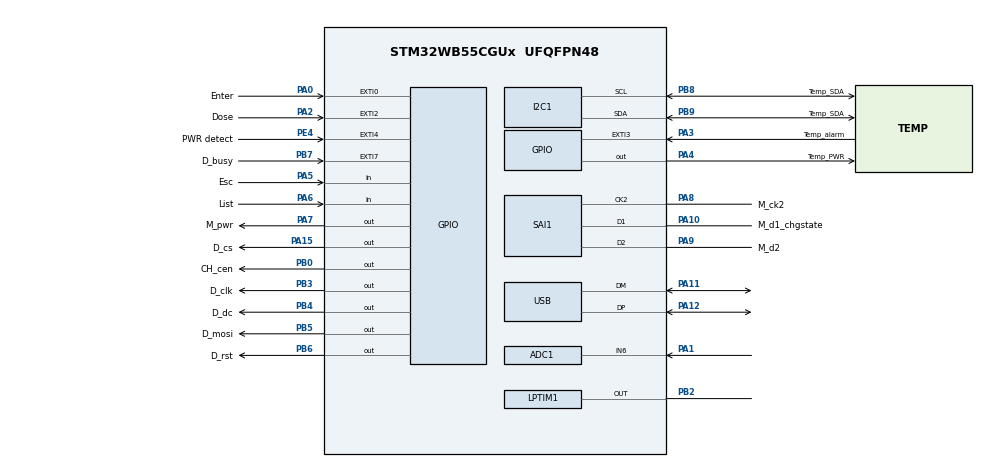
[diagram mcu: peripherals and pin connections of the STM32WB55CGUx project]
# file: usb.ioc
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ADC1.Channel-0\#ChannelRegularConversion=ADC_CHANNEL_6
ADC1.NbrOfConversion=1
ADC1.NbrOfConversionFlag=1
ADC1.OffsetNumber-0\#ChannelRegularConversion=ADC_OFFSET_NONE
ADC1.Rank-0\#ChannelRegularConversion=1
ADC1.SamplingTime-0\#ChannelRegularConversion=ADC_SAMPLETIME_640CYCLES_5
ADC1.master=1
Dma.Request0=SAI1_A
Dma.SAI1_A.0.Direction=DMA_PERIPH_TO_MEMORY
Dma.SAI1_A.0.EventEnable=DISABLE
Dma.SAI1_A.0.Instance=DMA1_Channel1
Dma.SAI1_A.0.MemDataAlignment=DMA_MDATAALIGN_WORD
Dma.SAI1_A.0.MemInc=DMA_MINC_ENABLE
Dma.SAI1_A.0.Mode=DMA_NORMAL
Dma.SAI1_A.0.PeriphDataAlignment=DMA_PDATAALIGN_WORD
Dma.SAI1_A.0.PeriphInc=DMA_PINC_DISABLE
Dma.SAI1_A.0.Polarity=HAL_DMAMUX_REQ_GEN_RISING
Dma.SAI1_A.0.Priority=DMA_PRIORITY_HIGH
Dma.SAI1_A.0.RequestNumber=1
Dma.SAI1_A.0.SignalID=NONE
Dma.SAI1_A.0.SyncEnable=DISABLE
Dma.SAI1_A.0.SyncPolarity=HAL_DMAMUX_SYNC_NO_EVENT
Dma.SAI1_A.0.SyncRequestNumber=1
Dma.SAI1_A.0.SyncSignalID=NONE
FATFS._FS_LOCK=1
FATFS._FS_MINIMIZE=2
I2C1.Speed=50
I2C1.Timing=0x10503EF9
LPTIM1.ClockPrescaler=LPTIM_PRESCALER_DIV32
Mcu.Family=STM32WB
Mcu.Name=STM32WB55CGUx
Mcu.Package=UFQFPN48
NVIC.DMA1_Channel1_IRQn=true\:0\:0\:false\:false\:true\:false\:true\:true
NVIC.EXTI0_IRQn=true\:0\:0\:false\:false\:true\:true\:true\:true
NVIC.EXTI2_IRQn=true\:0\:0\:false\:false\:true\:true\:true\:true
NVIC.EXTI3_IRQn=true\:0\:0\:false\:false\:true\:true\:true\:true
NVIC.EXTI4_IRQn=true\:0\:0\:false\:false\:true\:true\:true\:true
NVIC.EXTI9_5_IRQn=true\:0\:0\:false\:false\:true\:true\:true\:true
NVIC.FPU_IRQn=true\:0\:0\:false\:false\:true\:true\:false\:true
NVIC.PriorityGroup=NVIC_PRIORITYGROUP_4
NVIC.RTC_Alarm_IRQn=true\:0\:0\:false\:false\:true\:true\:true\:true
NVIC.RTC_WKUP_IRQn=true\:0\:0\:false\:false\:true\:true\:true\:true
NVIC.SAI1_IRQn=true\:0\:0\:false\:false\:true\:true\:true\:true
NVIC.USB_HP_IRQn=true\:0\:0\:false\:false\:true\:true\:true\:true
NVIC.USB_LP_IRQn=true\:0\:0\:false\:false\:true\:true\:true\:true
OSC_IN.Mode=HSE-External-Oscillator
OSC_IN.Signal=RCC_OSC_IN
OSC_OUT.Mode=HSE-External-Oscillator
OSC_OUT.Signal=RCC_OSC_OUT
PA0.GPIO_Label=Enter
PA0.Signal=GPXTI0
PA1.Signal=ADCx_IN6
PA10.GPIO_Label=M_d1_chgstate
PA10.Mode=PDM_Master_Mode_CK2
PA10.Signal=SAI1_D1
PA11.Mode=Device
PA11.Signal=USB_DM
PA12.Mode=Device
PA12.Signal=USB_DP
PA13.Mode=Serial_Wire
PA13.Signal=SYS_JTMS-SWDIO
PA14.Mode=Serial_Wire
PA14.Signal=SYS_JTCK-SWCLK
PA15.GPIO_Label=D_cs
PA15.Signal=GPIO_Output
PA2.GPIO_Label=Dose
PA2.GPIO_ModeDefaultEXTI=GPIO_MODE_IT_RISING_FALLING
PA2.GPIO_PuPd=GPIO_PULLUP
PA2.Signal=GPXTI2
PA3.GPIO_Label=Temp_alarm
PA3.GPIO_ModeDefaultEXTI=GPIO_MODE_IT_FALLING
PA3.GPIO_PuPd=GPIO_PULLUP
PA3.Signal=GPXTI3
PA4.GPIO_Label=Temp_PWR
PA4.GPIO_PuPd=GPIO_NOPULL
PA4.Signal=GPIO_Output
PA5.GPIO_Label=Esc
PA5.GPIO_PuPd=GPIO_PULLUP
PA5.Signal=GPIO_Input
PA6.GPIO_Label=List
PA6.GPIO_PuPd=GPIO_PULLUP
PA6.Signal=GPIO_Input
PA7.GPIO_Label=M_pwr
PA7.Signal=GPIO_Output
PA8.GPIO_Label=M_ck2
PA8.Mode=PDM_Master_Mode_CK2
PA8.Signal=SAI1_CK2
PA9.GPIO_Label=M_d2
PA9.Mode=3_4_MicroPhones
PA9.Signal=SAI1_D2
PB0.GPIO_Label=CH_cen
PB0.Signal=GPIO_Output
PB2.Mode=WaveformGeneration
PB2.Signal=LPTIM1_OUT
PB3.GPIO_Label=D_clk
PB3.Signal=GPIO_Output
PB4.GPIO_Label=D_dc
PB4.Signal=GPIO_Output
PB5.GPIO_Label=D_mosi
PB5.Signal=GPIO_Output
PB6.GPIO_Label=D_rst
PB6.Signal=GPIO_Output
PB7.GPIO_Label=D_busy
PB7.Signal=GPXTI7
PB8.GPIO_Label=Temp_SDA
PB8.GPIO_Pu=GPIO_PULLUP
PB8.Mode=I2C
PB8.Signal=I2C1_SCL
PB9.GPIO_Label=Temp_SDA
PB9.GPIO_Pu=GPIO_PULLUP
PB9.Mode=I2C
PB9.Signal=I2C1_SDA
PC14-OSC32_IN.Mode=LSE-External-Oscillator
PC14-OSC32_IN.Signal=RCC_OSC32_IN
PC15-OSC32_OUT.Mode=LSE-External-Oscillator
PC15-OSC32_OUT.Signal=RCC_OSC32_OUT
PE4.GPIO_Label=PWR detect
PE4.GPIO_ModeDefaultEXTI=GPIO_MODE_IT_RISING_FALLING
PE4.Signal=GPXTI4
ProjectManager.HeapSize=0x200
ProjectManager.StackSize=0x400
ProjectManager.TargetToolchain=STM32CubeIDE
RCC.ADCCLockSelection=RCC_ADCCLKSOURCE_SYSCLK
RCC.ADCFreq_Value=32000000
RCC.AHB2CLKDivider=RCC_SYSCLK_DIV8
RCC.AHBFreq_Value=32000000
RCC.APB1Freq_Value=32000000
RCC.APB1TimFreq_Value=32000000
RCC.APB2Freq_Value=32000000
RCC.APB2TimFreq_Value=32000000
RCC.APB3Freq_Value=16000000
RCC.CK48CLockSelection=RCC_USBCLKSOURCE_PLL
RCC.Cortex2_Div=SYSTICK_CLKSOURCE_HCLK_DIV8
RCC.CortexFreq_Value=32000000
RCC.EnableCSSLSE=true
RCC.HCLKFreq_Value=32000000
RCC.HSE_VALUE=32000000
RCC.HSI48_VALUE=48000000
RCC.HSI_VALUE=16000000
RCC.LSISource1=RCC_LSCOSOURCE_LSI2
RCC.MSIClockRange=RCC_MSIRANGE_8
RCC.PLLN=12
RCC.PLLP=RCC_PLLP_DIV4
RCC.PLLQ=RCC_PLLQ_DIV4
RCC.PLLR=RCC_PLLR_DIV6
RCC.PLLSAI1N=12
RCC.PLLSAI1P=RCC_PLLP_DIV4
RCC.PLLSAI1Q=RCC_PLLQ_DIV4
RCC.PLLSAI1R=RCC_PLLR_DIV4
RCC.RTCClockSelection=RCC_RTCCLKSOURCE_LSE
RCC.SMPSCLockSelection=RCC_SMPSCLKSOURCE_MSI
RCC.SYSCLKFreq_VALUE=32000000
RCC.SYSCLKSource=RCC_SYSCLKSOURCE_PLLCLK
RCC.USBFreq_Value=48000000
RCC.VCOOutputFreq_Value=192000000
RTC.Alarm-Alarm\ A=RTC_ALARM_A
SAI1.Activation=ENABLE
SAI1.AudioFrequency-PDM_Master_Mode_CK2=SAI_AUDIO_FREQUENCY_44K
SAI1.DataSize-PDM_Master_Mode_CK2=SAI_DATASIZE_8
SAI1.ErrorAudioFreq-PDM_Master_Mode_CK2=6.29 %
SAI1.FIFOThreshold-PDM_Master_Mode_CK2=SAI_FIFOTHRESHOLD_HF
SAI1.FSOffset-PDM_Master_Mode_CK2=SAI_FS_BEFOREFIRSTBIT
SAI1.FrameLength-PDM_Master_Mode_CK2=32
SAI1.Instance-PDM_Master_Mode_CK2=SAI$Index_Block_A
SAI1.MClockEnable-PDM_Master_Mode_CK2=SAI_MASTERCLOCK_DISABLE
SAI1.RealAudioFreq-PDM_Master_Mode_CK2=46.875 KHz
SAI1.SlotActive-PDM_Master_Mode_CK2=0x0000FFFF
SAI1.SlotNumber-PDM_Master_Mode_CK2=4
SAI1.SlotSize-PDM_Master_Mode_CK2=SAI_SLOTSIZE_DATASIZE
SAI1.VirtualMode-PDM_Master_Mode_CK2=VM_MASTER
SAI1.VirtualProtocol-PDM_Master_Mode_CK2=VM_PDM_PROTOCOL
SAI1.VirtualSlotActive-PDM_Master_Mode_CK2=SAI_SLOTACTIVE_ALL
SH.ADCx_IN6.0=ADC1_IN6,IN6-Single-Ended
USB_DEVICE.CLASS_NAME_FS=MSC
USB_DEVICE.VirtualMode=Msc
USB_DEVICE.VirtualModeFS=Msc_FS
VP_ADC1_Vref_Input.Mode=IN-Vrefint
VP_CRC_VS_CRC.Mode=CRC_Activate
VP_FATFS_VS_Generic.Mode=User_defined
VP_LPTIM1_VS_LPTIM_counterModeInternalClock.Mode=Counts__internal_clock_event_00
VP_MEMORYMAP_VS_MEMORYMAP.Mode=CurAppReg
VP_RTC_VS_RTC_Activate.Mode=RTC_Enabled
VP_RTC_VS_RTC_Alarm_A_Intern.Mode=Alarm A
VP_RTC_VS_RTC_Calendar.Mode=RTC_Calendar
VP_RTC_VS_RTC_WakeUp_intern.Mode=WakeUp
VP_USB_DEVICE_VS_USB_DEVICE_MSC_FS.Mode=MSC_FS
board=custom

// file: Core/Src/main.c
/* USER CODE BEGIN Header */
/**
  ******************************************************************************
  * @file           : main.c
  * @brief          : Main program body
  ******************************************************************************
  * @attention
  *
  * Copyright (c) 2025 STMicroelectronics.
  * All rights reserved.
  *
  * This software is licensed under terms that can be found in the LICENSE file
  * in the root directory of this software component.
  * If no LICENSE file comes with this software, it is provided AS-IS.
  *
  ******************************************************************************
  */
/* USER CODE END Header */
#include "main.h"
#include "app_fatfs.h"
#include "usb_device.h"

/* USER CODE BEGIN Includes */
#include "app_runtime.h"
/* main.c keeps CubeMX-generated peripheral bring-up; app_runtime.c owns the application flow. */
/* USER CODE END Includes */

ADC_HandleTypeDef hadc1;

CRC_HandleTypeDef hcrc;

I2C_HandleTypeDef hi2c1;

LPTIM_HandleTypeDef hlptim1;

RTC_HandleTypeDef hrtc;

SAI_HandleTypeDef hsai_BlockA1;
DMA_HandleTypeDef hdma_sai1_a;

void SystemClock_Config(void);
void PeriphCommonClock_Config(void);
static void MX_GPIO_Init(void);
static void MX_DMA_Init(void);
static void MX_LPTIM1_Init(void);
static void MX_ADC1_Init(void);
static void MX_RTC_Init(void);
static void MX_I2C1_Init(void);
static void MX_SAI1_Init(void);
static void MX_CRC_Init(void);

int main(void)
{

  /* MCU Configuration--------------------------------------------------------*/

  /* Reset of all peripherals, Initializes the Flash interface and the Systick. */
  HAL_Init();

  /* Configure the system clock */
  SystemClock_Config();

  /* Configure the peripherals common clocks */
  PeriphCommonClock_Config();

  /* Initialize all configured peripherals */
  MX_GPIO_Init();
  MX_DMA_Init();
  MX_LPTIM1_Init();
  if (MX_FATFS_Init() != APP_OK) {
    Error_Handler();
  }
  MX_ADC1_Init();
  MX_RTC_Init();
  MX_I2C1_Init();
  MX_SAI1_Init();
  MX_CRC_Init();
  /* USER CODE BEGIN 2 */
  /* Hand control to the higher-level runtime once all HAL handles exist. */
  if (!app_runtime_init(&hi2c1, &hlptim1)) {
    Error_Handler();
  }
  /* USER CODE END 2 */

  /* Infinite loop */
  while (1)
  {

    /* USER CODE BEGIN 3 */
    /* The application is organized as one cooperative superloop tick. */
    app_runtime_tick();
  }
  /* USER CODE END 3 */
}

void SystemClock_Config(void)
{
  RCC_OscInitTypeDef RCC_OscInitStruct = {0};
  RCC_ClkInitTypeDef RCC_ClkInitStruct = {0};

  /** Configure LSE Drive Capability
  */
  HAL_PWR_EnableBkUpAccess();
  __HAL_RCC_LSEDRIVE_CONFIG(RCC_LSEDRIVE_MEDIUMHIGH);

  /** Configure the main internal regulator output voltage
  */
  __HAL_PWR_VOLTAGESCALING_CONFIG(PWR_REGULATOR_VOLTAGE_SCALE1);

  /** Initializes the RCC Oscillators according to the specified parameters
  * in the RCC_OscInitTypeDef structure.
  */
  RCC_OscInitStruct.OscillatorType = RCC_OSCILLATORTYPE_HSI|RCC_OSCILLATORTYPE_HSE
                              |RCC_OSCILLATORTYPE_LSE|RCC_OSCILLATORTYPE_MSI;
  RCC_OscInitStruct.HSEState = RCC_HSE_ON;
  RCC_OscInitStruct.LSEState = RCC_LSE_ON;
  RCC_OscInitStruct.HSIState = RCC_HSI_ON;
  RCC_OscInitStruct.MSIState = RCC_MSI_ON;
  RCC_OscInitStruct.HSICalibrationValue = RCC_HSICALIBRATION_DEFAULT;
  RCC_OscInitStruct.MSICalibrationValue = RCC_MSICALIBRATION_DEFAULT;
  RCC_OscInitStruct.MSIClockRange = RCC_MSIRANGE_8;
  RCC_OscInitStruct.PLL.PLLState = RCC_PLL_ON;
  RCC_OscInitStruct.PLL.PLLSource = RCC_PLLSOURCE_MSI;
  RCC_OscInitStruct.PLL.PLLM = RCC_PLLM_DIV1;
  RCC_OscInitStruct.PLL.PLLN = 12;
  RCC_OscInitStruct.PLL.PLLP = RCC_PLLP_DIV4;
  RCC_OscInitStruct.PLL.PLLR = RCC_PLLR_DIV3;
  RCC_OscInitStruct.PLL.PLLQ = RCC_PLLQ_DIV4;
  if (HAL_RCC_OscConfig(&RCC_OscInitStruct) != HAL_OK)
  {
    Error_Handler();
  }

  /** Configure the SYSCLKSource, HCLK, PCLK1 and PCLK2 clocks dividers
  */
  RCC_ClkInitStruct.ClockType = RCC_CLOCKTYPE_HCLK4|RCC_CLOCKTYPE_HCLK2
                              |RCC_CLOCKTYPE_HCLK|RCC_CLOCKTYPE_SYSCLK
                              |RCC_CLOCKTYPE_PCLK1|RCC_CLOCKTYPE_PCLK2;
  RCC_ClkInitStruct.SYSCLKSource = RCC_SYSCLKSOURCE_PLLCLK;
  RCC_ClkInitStruct.AHBCLKDivider = RCC_SYSCLK_DIV1;
  RCC_ClkInitStruct.APB1CLKDivider = RCC_HCLK_DIV1;
  RCC_ClkInitStruct.APB2CLKDivider = RCC_HCLK_DIV1;
  RCC_ClkInitStruct.AHBCLK2Divider = RCC_SYSCLK_DIV8;
  RCC_ClkInitStruct.AHBCLK4Divider = RCC_SYSCLK_DIV1;

  if (HAL_RCC_ClockConfig(&RCC_ClkInitStruct, FLASH_LATENCY_3) != HAL_OK)
  {
    Error_Handler();
  }

  /** Enables the Clock Security System
  */
  HAL_RCCEx_EnableLSECSS();

  /** Enable MSI Auto calibration
  */
  HAL_RCCEx_EnableMSIPLLMode();
}

void PeriphCommonClock_Config(void)
{
  RCC_PeriphCLKInitTypeDef PeriphClkInitStruct = {0};

  /** Initializes the peripherals clock
  */
  PeriphClkInitStruct.PeriphClockSelection = RCC_PERIPHCLK_SMPS;
  PeriphClkInitStruct.SmpsClockSelection = RCC_SMPSCLKSOURCE_MSI;
  PeriphClkInitStruct.SmpsDivSelection = RCC_SMPSCLKDIV_RANGE1;

  if (HAL_RCCEx_PeriphCLKConfig(&PeriphClkInitStruct) != HAL_OK)
  {
    Error_Handler();
  }
}

static void MX_ADC1_Init(void)
{

  ADC_ChannelConfTypeDef sConfig = {0};

  /** Common config
  */
  hadc1.Instance = ADC1;
  hadc1.Init.ClockPrescaler = ADC_CLOCK_ASYNC_DIV1;
  hadc1.Init.Resolution = ADC_RESOLUTION_12B;
  hadc1.Init.DataAlign = ADC_DATAALIGN_RIGHT;
  hadc1.Init.ScanConvMode = ADC_SCAN_DISABLE;
  hadc1.Init.EOCSelection = ADC_EOC_SINGLE_CONV;
  hadc1.Init.LowPowerAutoWait = DISABLE;
  hadc1.Init.ContinuousConvMode = DISABLE;
  hadc1.Init.NbrOfConversion = 1;
  hadc1.Init.DiscontinuousConvMode = DISABLE;
  hadc1.Init.ExternalTrigConv = ADC_SOFTWARE_START;
  hadc1.Init.ExternalTrigConvEdge = ADC_EXTERNALTRIGCONVEDGE_NONE;
  hadc1.Init.DMAContinuousRequests = DISABLE;
  hadc1.Init.Overrun = ADC_OVR_DATA_PRESERVED;
  hadc1.Init.OversamplingMode = DISABLE;
  if (HAL_ADC_Init(&hadc1) != HAL_OK)
  {
    Error_Handler();
  }

  /** Configure Regular Channel
  */
  sConfig.Channel = ADC_CHANNEL_6;
  sConfig.Rank = ADC_REGULAR_RANK_1;
  sConfig.SamplingTime = ADC_SAMPLETIME_640CYCLES_5;
  sConfig.SingleDiff = ADC_SINGLE_ENDED;
  sConfig.OffsetNumber = ADC_OFFSET_NONE;
  sConfig.Offset = 0;
  if (HAL_ADC_ConfigChannel(&hadc1, &sConfig) != HAL_OK)
  {
    Error_Handler();
  }

}

static void MX_CRC_Init(void)
{

  hcrc.Instance = CRC;
  hcrc.Init.DefaultPolynomialUse = DEFAULT_POLYNOMIAL_ENABLE;
  hcrc.Init.DefaultInitValueUse = DEFAULT_INIT_VALUE_ENABLE;
  hcrc.Init.InputDataInversionMode = CRC_INPUTDATA_INVERSION_NONE;
  hcrc.Init.OutputDataInversionMode = CRC_OUTPUTDATA_INVERSION_DISABLE;
  hcrc.InputDataFormat = CRC_INPUTDATA_FORMAT_BYTES;
  if (HAL_CRC_Init(&hcrc) != HAL_OK)
  {
    Error_Handler();
  }

}

static void MX_I2C1_Init(void)
{

  hi2c1.Instance = I2C1;
  hi2c1.Init.Timing = 0x10503EF9;
  hi2c1.Init.OwnAddress1 = 0;
  hi2c1.Init.AddressingMode = I2C_ADDRESSINGMODE_7BIT;
  hi2c1.Init.DualAddressMode = I2C_DUALADDRESS_DISABLE;
  hi2c1.Init.OwnAddress2 = 0;
  hi2c1.Init.OwnAddress2Masks = I2C_OA2_NOMASK;
  hi2c1.Init.GeneralCallMode = I2C_GENERALCALL_DISABLE;
  hi2c1.Init.NoStretchMode = I2C_NOSTRETCH_DISABLE;
  if (HAL_I2C_Init(&hi2c1) != HAL_OK)
  {
    Error_Handler();
  }

  /** Configure Analogue filter
  */
  if (HAL_I2CEx_ConfigAnalogFilter(&hi2c1, I2C_ANALOGFILTER_ENABLE) != HAL_OK)
  {
    Error_Handler();
  }

  /** Configure Digital filter
  */
  if (HAL_I2CEx_ConfigDigitalFilter(&hi2c1, 0) != HAL_OK)
  {
    Error_Handler();
  }

}

static void MX_LPTIM1_Init(void)
{

  hlptim1.Instance = LPTIM1;
  hlptim1.Init.Clock.Source = LPTIM_CLOCKSOURCE_APBCLOCK_LPOSC;
  hlptim1.Init.Clock.Prescaler = LPTIM_PRESCALER_DIV32;
  hlptim1.Init.Trigger.Source = LPTIM_TRIGSOURCE_SOFTWARE;
  hlptim1.Init.OutputPolarity = LPTIM_OUTPUTPOLARITY_HIGH;
  hlptim1.Init.UpdateMode = LPTIM_UPDATE_IMMEDIATE;
  hlptim1.Init.CounterSource = LPTIM_COUNTERSOURCE_INTERNAL;
  hlptim1.Init.Input1Source = LPTIM_INPUT1SOURCE_GPIO;
  hlptim1.Init.Input2Source = LPTIM_INPUT2SOURCE_GPIO;
  if (HAL_LPTIM_Init(&hlptim1) != HAL_OK)
  {
    Error_Handler();
  }

}

static void MX_RTC_Init(void)
{

  RTC_TimeTypeDef sTime = {0};
  RTC_DateTypeDef sDate = {0};
  RTC_AlarmTypeDef sAlarm = {0};

  /** Initialize RTC Only
  */
  hrtc.Instance = RTC;
  hrtc.Init.HourFormat = RTC_HOURFORMAT_24;
  hrtc.Init.AsynchPrediv = 127;
  hrtc.Init.SynchPrediv = 255;
  hrtc.Init.OutPut = RTC_OUTPUT_DISABLE;
  hrtc.Init.OutPutPolarity = RTC_OUTPUT_POLARITY_HIGH;
  hrtc.Init.OutPutType = RTC_OUTPUT_TYPE_OPENDRAIN;
  hrtc.Init.OutPutRemap = RTC_OUTPUT_REMAP_NONE;
  if (HAL_RTC_Init(&hrtc) != HAL_OK)
  {
    Error_Handler();
  }

  /** Initialize RTC and set the Time and Date
  */
  sTime.Hours = 0x0;
  sTime.Minutes = 0x0;
  sTime.Seconds = 0x0;
  sTime.SubSeconds = 0x0;
  sTime.DayLightSaving = RTC_DAYLIGHTSAVING_NONE;
  sTime.StoreOperation = RTC_STOREOPERATION_RESET;
  if (HAL_RTC_SetTime(&hrtc, &sTime, RTC_FORMAT_BCD) != HAL_OK)
  {
    Error_Handler();
  }
  sDate.WeekDay = RTC_WEEKDAY_MONDAY;
  sDate.Month = RTC_MONTH_JANUARY;
  sDate.Date = 0x1;
  sDate.Year = 0x0;
  if (HAL_RTC_SetDate(&hrtc, &sDate, RTC_FORMAT_BCD) != HAL_OK)
  {
    Error_Handler();
  }

  /** Enable the Alarm A
  */
  sAlarm.AlarmTime.Hours = 0x0;
  sAlarm.AlarmTime.Minutes = 0x0;
  sAlarm.AlarmTime.Seconds = 0x0;
  sAlarm.AlarmTime.SubSeconds = 0x0;
  sAlarm.AlarmTime.DayLightSaving = RTC_DAYLIGHTSAVING_NONE;
  sAlarm.AlarmTime.StoreOperation = RTC_STOREOPERATION_RESET;
  sAlarm.AlarmMask = RTC_ALARMMASK_NONE;
  sAlarm.AlarmSubSecondMask = RTC_ALARMSUBSECONDMASK_ALL;
  sAlarm.AlarmDateWeekDaySel = RTC_ALARMDATEWEEKDAYSEL_DATE;
  sAlarm.AlarmDateWeekDay = 0x1;
  sAlarm.Alarm = RTC_ALARM_A;
  if (HAL_RTC_SetAlarm_IT(&hrtc, &sAlarm, RTC_FORMAT_BCD) != HAL_OK)
  {
    Error_Handler();
  }

  /** Enable the WakeUp
  */
  if (HAL_RTCEx_SetWakeUpTimer_IT(&hrtc, 0, RTC_WAKEUPCLOCK_RTCCLK_DIV16) != HAL_OK)
  {
    Error_Handler();
  }

}

static void MX_SAI1_Init(void)
{

  hsai_BlockA1.Instance = SAI1_Block_A;
  hsai_BlockA1.Init.Protocol = SAI_FREE_PROTOCOL;
  hsai_BlockA1.Init.AudioMode = SAI_MODEMASTER_RX;
  hsai_BlockA1.Init.DataSize = SAI_DATASIZE_8;
  hsai_BlockA1.Init.FirstBit = SAI_FIRSTBIT_MSB;
  hsai_BlockA1.Init.ClockStrobing = SAI_CLOCKSTROBING_FALLINGEDGE;
  hsai_BlockA1.Init.Synchro = SAI_ASYNCHRONOUS;
  hsai_BlockA1.Init.OutputDrive = SAI_OUTPUTDRIVE_DISABLE;
  hsai_BlockA1.Init.NoDivider = SAI_MASTERDIVIDER_ENABLE;
  hsai_BlockA1.Init.MckOverSampling = SAI_MCK_OVERSAMPLING_DISABLE;
  hsai_BlockA1.Init.FIFOThreshold = SAI_FIFOTHRESHOLD_HF;
  hsai_BlockA1.Init.AudioFrequency = SAI_AUDIO_FREQUENCY_44K;
  hsai_BlockA1.Init.MonoStereoMode = SAI_STEREOMODE;
  hsai_BlockA1.Init.CompandingMode = SAI_NOCOMPANDING;
  hsai_BlockA1.Init.PdmInit.Activation = ENABLE;
  hsai_BlockA1.Init.PdmInit.MicPairsNbr = 2;
  hsai_BlockA1.Init.PdmInit.ClockEnable = SAI_PDM_CLOCK2_ENABLE;
  hsai_BlockA1.FrameInit.FrameLength = 32;
  hsai_BlockA1.FrameInit.ActiveFrameLength = 1;
  hsai_BlockA1.FrameInit.FSDefinition = SAI_FS_STARTFRAME;
  hsai_BlockA1.FrameInit.FSPolarity = SAI_FS_ACTIVE_LOW;
  hsai_BlockA1.FrameInit.FSOffset = SAI_FS_BEFOREFIRSTBIT;
  hsai_BlockA1.SlotInit.FirstBitOffset = 0;
  hsai_BlockA1.SlotInit.SlotSize = SAI_SLOTSIZE_DATASIZE;
  hsai_BlockA1.SlotInit.SlotNumber = 4;
  hsai_BlockA1.SlotInit.SlotActive = 0x0000FFFF;
  if (HAL_SAI_Init(&hsai_BlockA1) != HAL_OK)
  {
    Error_Handler();
  }

}

static void MX_DMA_Init(void)
{

  /* DMA controller clock enable */
  __HAL_RCC_DMAMUX1_CLK_ENABLE();
  __HAL_RCC_DMA1_CLK_ENABLE();

  /* DMA interrupt init */
  /* DMA1_Channel1_IRQn interrupt configuration */
  HAL_NVIC_SetPriority(DMA1_Channel1_IRQn, 0, 0);
  HAL_NVIC_EnableIRQ(DMA1_Channel1_IRQn);

}

static void MX_GPIO_Init(void)
{
  GPIO_InitTypeDef GPIO_InitStruct = {0};
  /* USER CODE BEGIN MX_GPIO_Init_1 */
 //__HAL_RCC_GPIOE_CLK_ENABLE();  // kvôli PE4 (VBUS sense)
  /* USER CODE END MX_GPIO_Init_1 */

  /* GPIO Ports Clock Enable */
  __HAL_RCC_GPIOC_CLK_ENABLE();
  __HAL_RCC_GPIOB_CLK_ENABLE();
  __HAL_RCC_GPIOA_CLK_ENABLE();
  __HAL_RCC_GPIOE_CLK_ENABLE();

  /*Configure GPIO pin Output Level */
  HAL_GPIO_WritePin(GPIOA, Temp_PWR_Pin|M_pwr_Pin|D_cs_Pin, GPIO_PIN_RESET);

  /*Configure GPIO pin Output Level */
  HAL_GPIO_WritePin(GPIOB, CH_cen_Pin|D_clk_Pin|D_dc_Pin|D_mosi_Pin
                          |D_rst_Pin, GPIO_PIN_RESET);

  /*Configure GPIO pin : Enter_Pin */
  GPIO_InitStruct.Pin = Enter_Pin;
  GPIO_InitStruct.Mode = GPIO_MODE_IT_RISING;
  GPIO_InitStruct.Pull = GPIO_NOPULL;
  HAL_GPIO_Init(Enter_GPIO_Port, &GPIO_InitStruct);

  /*Configure GPIO pin : Dose_Pin */
  GPIO_InitStruct.Pin = Dose_Pin;
  GPIO_InitStruct.Mode = GPIO_MODE_IT_RISING_FALLING;
  GPIO_InitStruct.Pull = GPIO_PULLUP;
  HAL_GPIO_Init(Dose_GPIO_Port, &GPIO_InitStruct);

  /*Configure GPIO pin : Temp_alarm_Pin */
  GPIO_InitStruct.Pin = Temp_alarm_Pin;
  GPIO_InitStruct.Mode = GPIO_MODE_IT_FALLING;
  GPIO_InitStruct.Pull = GPIO_PULLUP;
  HAL_GPIO_Init(Temp_alarm_GPIO_Port, &GPIO_InitStruct);

  /*Configure GPIO pins : Temp_PWR_Pin M_pwr_Pin D_cs_Pin */
  GPIO_InitStruct.Pin = Temp_PWR_Pin|M_pwr_Pin|D_cs_Pin;
  GPIO_InitStruct.Mode = GPIO_MODE_OUTPUT_PP;
  GPIO_InitStruct.Pull = GPIO_NOPULL;
  GPIO_InitStruct.Speed = GPIO_SPEED_FREQ_LOW;
  HAL_GPIO_Init(GPIOA, &GPIO_InitStruct);

  /*Configure GPIO pins : Esc_Pin List_Pin */
  GPIO_InitStruct.Pin = Esc_Pin|List_Pin;
  GPIO_InitStruct.Mode = GPIO_MODE_INPUT;
  GPIO_InitStruct.Pull = GPIO_PULLUP;
  HAL_GPIO_Init(GPIOA, &GPIO_InitStruct);

  /*Configure GPIO pins : CH_cen_Pin D_clk_Pin D_dc_Pin D_mosi_Pin
                           D_rst_Pin */
  GPIO_InitStruct.Pin = CH_cen_Pin|D_clk_Pin|D_dc_Pin|D_mosi_Pin
                          |D_rst_Pin;
  GPIO_InitStruct.Mode = GPIO_MODE_OUTPUT_PP;
  GPIO_InitStruct.Pull = GPIO_NOPULL;
  GPIO_InitStruct.Speed = GPIO_SPEED_FREQ_LOW;
  HAL_GPIO_Init(GPIOB, &GPIO_InitStruct);

  /*Configure GPIO pin : PWR_detect_Pin */
  GPIO_InitStruct.Pin = PWR_detect_Pin;
  GPIO_InitStruct.Mode = GPIO_MODE_IT_RISING_FALLING;
  GPIO_InitStruct.Pull = GPIO_NOPULL;
  HAL_GPIO_Init(PWR_detect_GPIO_Port, &GPIO_InitStruct);

  /*Configure GPIO pin : D_busy_Pin */
  GPIO_InitStruct.Pin = D_busy_Pin;
  GPIO_InitStruct.Mode = GPIO_MODE_IT_RISING;
  GPIO_InitStruct.Pull = GPIO_NOPULL;
  HAL_GPIO_Init(D_busy_GPIO_Port, &GPIO_InitStruct);

  /* EXTI interrupt init*/
  HAL_NVIC_SetPriority(EXTI0_IRQn, 0, 0);
  HAL_NVIC_EnableIRQ(EXTI0_IRQn);

  HAL_NVIC_SetPriority(EXTI2_IRQn, 0, 0);
  HAL_NVIC_EnableIRQ(EXTI2_IRQn);

  HAL_NVIC_SetPriority(EXTI3_IRQn, 0, 0);
  HAL_NVIC_EnableIRQ(EXTI3_IRQn);

  HAL_NVIC_SetPriority(EXTI4_IRQn, 0, 0);
  HAL_NVIC_EnableIRQ(EXTI4_IRQn);

  HAL_NVIC_SetPriority(EXTI9_5_IRQn, 0, 0);
  HAL_NVIC_EnableIRQ(EXTI9_5_IRQn);

  /* USER CODE BEGIN MX_GPIO_Init_2 */
  // PA0 = ENTER (tlačidlo proti GND -> pull-up + zostupna hrana)
  GPIO_InitStruct.Pin  = Enter_Pin;
  GPIO_InitStruct.Mode = GPIO_MODE_IT_FALLING;
  GPIO_InitStruct.Pull = GPIO_PULLUP;
  HAL_GPIO_Init(Enter_GPIO_Port, &GPIO_InitStruct);

  // PA2 = DOSE (všetky tlačidlá proti GND → potrebuje PULLUP)
  GPIO_InitStruct.Pin  = Dose_Pin;
  GPIO_InitStruct.Mode = GPIO_MODE_IT_RISING_FALLING;
  GPIO_InitStruct.Pull = GPIO_PULLUP;
  HAL_GPIO_Init(Dose_GPIO_Port, &GPIO_InitStruct);

  GPIO_InitStruct.Pin  = Temp_Alert_Pin;
  GPIO_InitStruct.Mode = GPIO_MODE_IT_FALLING;
  GPIO_InitStruct.Pull = GPIO_PULLUP;
  HAL_GPIO_Init(Temp_Alert_GPIO_Port, &GPIO_InitStruct);

  HAL_NVIC_SetPriority(EXTI3_IRQn, 5, 0);
  HAL_NVIC_EnableIRQ(EXTI3_IRQn);
  HAL_NVIC_SetPriority(EXTI0_IRQn, 5, 0);
  HAL_NVIC_EnableIRQ(EXTI0_IRQn);
  // NVIC pre EXTI2 (PA2)
  HAL_NVIC_SetPriority(EXTI2_IRQn, 5, 0);
  HAL_NVIC_EnableIRQ(EXTI2_IRQn);
  /* USER CODE END MX_GPIO_Init_2 */
}

/* USER CODE BEGIN 4 */
/* Hardware callbacks are forwarded to app_runtime so policy stays out of generated code. */
void HAL_RTCEx_WakeUpTimerEventCallback(RTC_HandleTypeDef *rtc)
{
  (void)rtc;
  app_runtime_on_rtc_wakeup();
}

void HAL_GPIO_EXTI_Callback(uint16_t GPIO_Pin)
{
  app_runtime_on_exti(GPIO_Pin);
}

void HAL_PWR_PVDCallback(void)
{
  app_runtime_on_pvd();
}

void HAL_PWREx_PVD_PVMCallback(PWR_PVMTypeDef PVD_PVM)
{
  (void)PVD_PVM;
  app_runtime_on_pvd();
}

/* USER CODE END 4 */

void Error_Handler(void)
{
  __disable_irq();
  while (1)
  {
  }
}
